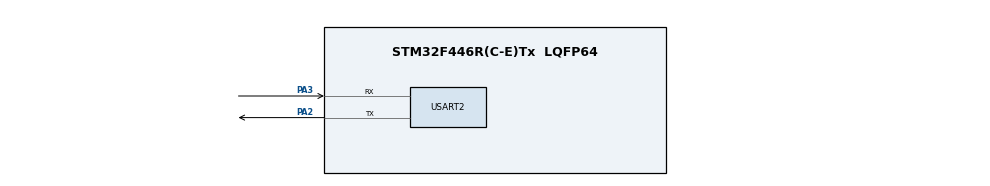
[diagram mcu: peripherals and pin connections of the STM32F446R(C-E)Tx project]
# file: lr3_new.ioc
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Mcu.Family=STM32F4
RCC.VCOOutputFreq_Value=192000000
RCC.CortexFreq_Value=16000000
Mcu.Name=STM32F446R(C-E)Tx
PA2.Signal=USART2_TX
NVIC.USART2_IRQn=true\:0\:0\:false\:false\:true\:true\:true
Mcu.Package=LQFP64
ProjectManager.StackSize=0x400
USART2.VirtualMode=VM_ASYNC
PA3.Mode=Asynchronous
ProjectManager.HeapSize=0x200
ProjectManager.TargetToolchain=STM32CubeIDE
NVIC.PriorityGroup=NVIC_PRIORITYGROUP_4
PA2.Mode=Asynchronous
RCC.USBFreq_Value=96000000
PA3.Signal=USART2_RX
board=custom

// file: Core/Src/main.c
/* USER CODE BEGIN Header */
/**
  ******************************************************************************
  * @file           : main.c
  * @brief          : Main program body
  ******************************************************************************
  * @attention
  *
  * <h2><center>&copy; Copyright (c) 2022 STMicroelectronics.
  * All rights reserved.</center></h2>
  *
  * This software component is licensed by ST under BSD 3-Clause license,
  * the "License"; You may not use this file except in compliance with the
  * License. You may obtain a copy of the License at:
  *                        opensource.org/licenses/BSD-3-Clause
  *
  ******************************************************************************
  */
/* USER CODE END Header */
#include "main.h"
#include <stdlib.h>
#include <math.h>
#include <string.h>
#include <stdint.h>

UART_HandleTypeDef huart2;

void SystemClock_Config(void);
static void MX_GPIO_Init(void);
static void MX_USART2_UART_Init(void);

/* USER CODE BEGIN 0 */

void set_number(int64_t);
void reset_number();
void set_screen(int64_t);
void set_minus(int64_t);
void set_long_number(int64_t);
void reset_all();
int64_t unpack_data(uint8_t*);
void pack_data(double) ;
void set_to_empty(uint8_t*, uint16_t);
void set_float_number(double);
int64_t get_float_part(double);
void add_minus();
void add_number(int64_t);
void add_dot();
void set_dot();

/* USER CODE END 0 */

int64_t count = 0;
double answer = 0;
uint8_t input_data[] = {'N', 0, 0, 0, 0, 0, 0, 'E'};
uint8_t output_data[] = {'N', 0, 0, 0, 0, 0, 50, 'E'};
uint8_t empty_data[] = {'N', 0, 0, 0, 0, 0, 0, 'E'};
uint16_t input_package_size = 8;
uint16_t output_package_size = 8;
uint8_t pos = 1;

int main(void)
{

  /* MCU Configuration--------------------------------------------------------*/

  /* Reset of all peripherals, Initializes the Flash interface and the Systick. */
  HAL_Init();

  /* Configure the system clock */
  SystemClock_Config();

  /* Initialize all configured peripherals */
  MX_GPIO_Init();
  MX_USART2_UART_Init();

  /* Infinite loop */
  /* USER CODE BEGIN WHILE */

  reset_all();
  set_long_number(count);

  HAL_UART_Receive_IT(&huart2, input_data, input_package_size);

  while (1)
  {

	//  HAL_UART_Transmit_IT(&huart2, output_data, output_package_size);
	  HAL_Delay(1);
	  set_float_number(answer);

    /* USER CODE END WHILE */

  }
}

int64_t unpack_data(uint8_t* data){
	return (int64_t)((100000*(int64_t)(data[1] - '0'))+(10000*(int64_t)(data[2] - '0')) + (1000*(int64_t)(data[4] - '0')) + (100*(int64_t)(data[4] - '0'))+(10*(int64_t)(data[5] - '0')) + (int64_t)(data[6]-'0'));
}

void pack_data(double data) {
	if (data < 0) add_minus();
	if (abs(data) == 1) {
		add_number(1);
	} else {
		add_number(0);
		add_dot();
		add_number((int)(abs(data*1000)));
	}

}

void add_minus() {
	output_data[pos] = 45;
	pos++;
}

void add_dot() {
	output_data[pos] = 46;
	pos++;
}

void add_number(int64_t num) {
	if (num == 0) {
		output_data[pos] = 48;
		pos++;
		return;
	}

	int64_t buffer = num;
	int64_t digit_count = 0;

	for (int i = 1; i <= 5; ++i) {
	    if (buffer % 10) digit_count = i;
	    buffer /= 10;
	}

	int64_t counter = 0;
	int64_t module = pow(10, digit_count-1);

	while (counter < digit_count) {
		output_data[pos] = num / module + 48;
		num = num % module;
		module = module/10;
		counter++;
		pos++;
	}
}

void set_to_empty(uint8_t* array, uint16_t input_package_size) {
	for (int64_t i = 1; i < input_package_size-1; i++) {
		array[i] = 0;
	}
}

void set_number(int64_t num) {
    switch (num) {
        case 0:
            HAL_GPIO_WritePin(GPIOD, GPIO_PIN_2, GPIO_PIN_RESET);
            HAL_GPIO_WritePin(GPIOA, GPIO_PIN_6, GPIO_PIN_RESET);
            HAL_GPIO_WritePin(GPIOA, GPIO_PIN_12, GPIO_PIN_RESET);
            HAL_GPIO_WritePin(GPIOA, GPIO_PIN_11, GPIO_PIN_RESET);
            HAL_GPIO_WritePin(GPIOC, GPIO_PIN_10, GPIO_PIN_RESET);
            HAL_GPIO_WritePin(GPIOC, GPIO_PIN_11, GPIO_PIN_RESET);
            break;
        case 1:
            HAL_GPIO_WritePin(GPIOA, GPIO_PIN_12, GPIO_PIN_RESET);
	        HAL_GPIO_WritePin(GPIOA, GPIO_PIN_11, GPIO_PIN_RESET);
            break;
        case 2:
            HAL_GPIO_WritePin(GPIOC, GPIO_PIN_12, GPIO_PIN_RESET);
	        HAL_GPIO_WritePin(GPIOA, GPIO_PIN_6, GPIO_PIN_RESET);
	        HAL_GPIO_WritePin(GPIOA, GPIO_PIN_12, GPIO_PIN_RESET);
	        HAL_GPIO_WritePin(GPIOC, GPIO_PIN_10, GPIO_PIN_RESET);
	        HAL_GPIO_WritePin(GPIOC, GPIO_PIN_11, GPIO_PIN_RESET);
            break;
        case 3:
            HAL_GPIO_WritePin(GPIOC, GPIO_PIN_12, GPIO_PIN_RESET);
            HAL_GPIO_WritePin(GPIOA, GPIO_PIN_6, GPIO_PIN_RESET);
            HAL_GPIO_WritePin(GPIOA, GPIO_PIN_12, GPIO_PIN_RESET);
            HAL_GPIO_WritePin(GPIOC, GPIO_PIN_10, GPIO_PIN_RESET);
            HAL_GPIO_WritePin(GPIOA, GPIO_PIN_11, GPIO_PIN_RESET);
            break;
        case 4:
            HAL_GPIO_WritePin(GPIOD, GPIO_PIN_2, GPIO_PIN_RESET);
	        HAL_GPIO_WritePin(GPIOC, GPIO_PIN_12, GPIO_PIN_RESET);
	        HAL_GPIO_WritePin(GPIOA, GPIO_PIN_12, GPIO_PIN_RESET);
	        HAL_GPIO_WritePin(GPIOA, GPIO_PIN_11, GPIO_PIN_RESET);
            break;
        case 5:
            HAL_GPIO_WritePin(GPIOC, GPIO_PIN_12, GPIO_PIN_RESET);
            HAL_GPIO_WritePin(GPIOD, GPIO_PIN_2, GPIO_PIN_RESET);
            HAL_GPIO_WritePin(GPIOA, GPIO_PIN_6, GPIO_PIN_RESET);
            HAL_GPIO_WritePin(GPIOA, GPIO_PIN_11, GPIO_PIN_RESET);
            HAL_GPIO_WritePin(GPIOC, GPIO_PIN_10, GPIO_PIN_RESET);
            break;
        case 6:
            HAL_GPIO_WritePin(GPIOC, GPIO_PIN_12, GPIO_PIN_RESET);
            HAL_GPIO_WritePin(GPIOD, GPIO_PIN_2, GPIO_PIN_RESET);
            HAL_GPIO_WritePin(GPIOA, GPIO_PIN_6, GPIO_PIN_RESET);
            HAL_GPIO_WritePin(GPIOA, GPIO_PIN_11, GPIO_PIN_RESET);
            HAL_GPIO_WritePin(GPIOC, GPIO_PIN_10, GPIO_PIN_RESET);
            HAL_GPIO_WritePin(GPIOC, GPIO_PIN_11, GPIO_PIN_RESET);
            break;
        case 7:
            HAL_GPIO_WritePin(GPIOA, GPIO_PIN_6, GPIO_PIN_RESET);
            HAL_GPIO_WritePin(GPIOA, GPIO_PIN_12, GPIO_PIN_RESET);
            HAL_GPIO_WritePin(GPIOA, GPIO_PIN_11, GPIO_PIN_RESET);
            break;
        case 8:
            HAL_GPIO_WritePin(GPIOC, GPIO_PIN_12, GPIO_PIN_RESET);
            HAL_GPIO_WritePin(GPIOD, GPIO_PIN_2, GPIO_PIN_RESET);
            HAL_GPIO_WritePin(GPIOA, GPIO_PIN_6, GPIO_PIN_RESET);
            HAL_GPIO_WritePin(GPIOA, GPIO_PIN_12, GPIO_PIN_RESET);
            HAL_GPIO_WritePin(GPIOA, GPIO_PIN_11, GPIO_PIN_RESET);
            HAL_GPIO_WritePin(GPIOC, GPIO_PIN_10, GPIO_PIN_RESET);
            HAL_GPIO_WritePin(GPIOC, GPIO_PIN_11, GPIO_PIN_RESET);
            break;
        case 9:
            HAL_GPIO_WritePin(GPIOC, GPIO_PIN_12, GPIO_PIN_RESET);
            HAL_GPIO_WritePin(GPIOD, GPIO_PIN_2, GPIO_PIN_RESET);
            HAL_GPIO_WritePin(GPIOA, GPIO_PIN_6, GPIO_PIN_RESET);
            HAL_GPIO_WritePin(GPIOA, GPIO_PIN_12, GPIO_PIN_RESET);
            HAL_GPIO_WritePin(GPIOA, GPIO_PIN_11, GPIO_PIN_RESET);
            HAL_GPIO_WritePin(GPIOC, GPIO_PIN_10, GPIO_PIN_RESET);
            break;
    }
}

void reset_number() {
    HAL_GPIO_WritePin(GPIOC, GPIO_PIN_12, GPIO_PIN_SET);
    HAL_GPIO_WritePin(GPIOD, GPIO_PIN_2, GPIO_PIN_SET);
    HAL_GPIO_WritePin(GPIOA, GPIO_PIN_6, GPIO_PIN_SET);
    HAL_GPIO_WritePin(GPIOA, GPIO_PIN_12, GPIO_PIN_SET);
    HAL_GPIO_WritePin(GPIOA, GPIO_PIN_11, GPIO_PIN_SET);
    HAL_GPIO_WritePin(GPIOC, GPIO_PIN_10, GPIO_PIN_SET);
    HAL_GPIO_WritePin(GPIOC, GPIO_PIN_11, GPIO_PIN_SET);
    HAL_GPIO_WritePin(GPIOA, GPIO_PIN_15, GPIO_PIN_SET);
}

void set_screen(int64_t num) {
    switch (num) {
        case 1:
            HAL_GPIO_WritePin(GPIOB, GPIO_PIN_1, GPIO_PIN_SET);
            HAL_GPIO_WritePin(GPIOB, GPIO_PIN_3, GPIO_PIN_SET);
            HAL_GPIO_WritePin(GPIOA, GPIO_PIN_10, GPIO_PIN_SET);
            HAL_GPIO_WritePin(GPIOC, GPIO_PIN_4, GPIO_PIN_RESET);
            break;
        case 2:
            HAL_GPIO_WritePin(GPIOB, GPIO_PIN_1, GPIO_PIN_SET);
            HAL_GPIO_WritePin(GPIOB, GPIO_PIN_3, GPIO_PIN_SET);
            HAL_GPIO_WritePin(GPIOA, GPIO_PIN_10, GPIO_PIN_RESET);
            HAL_GPIO_WritePin(GPIOC, GPIO_PIN_4, GPIO_PIN_SET);
            break;
        case 3:
            HAL_GPIO_WritePin(GPIOB, GPIO_PIN_1, GPIO_PIN_SET);
            HAL_GPIO_WritePin(GPIOB, GPIO_PIN_3, GPIO_PIN_RESET);
            HAL_GPIO_WritePin(GPIOA, GPIO_PIN_10, GPIO_PIN_SET);
            HAL_GPIO_WritePin(GPIOC, GPIO_PIN_4, GPIO_PIN_SET);
            break;
        case 4:
            HAL_GPIO_WritePin(GPIOB, GPIO_PIN_1, GPIO_PIN_RESET);
            HAL_GPIO_WritePin(GPIOB, GPIO_PIN_3, GPIO_PIN_SET);
            HAL_GPIO_WritePin(GPIOA, GPIO_PIN_10, GPIO_PIN_SET);
            HAL_GPIO_WritePin(GPIOC, GPIO_PIN_4, GPIO_PIN_SET);
            break;
    }
}

void set_long_number(int64_t num) {

    int64_t digit_count = 0;
    int64_t buffer = (int64_t) abs(num);

    for (int i = 1; i <= 4; ++i) {
        if (buffer % 10) digit_count = i;
        buffer /= 10;
    }

    if (num == 0) {
    	digit_count = 2;
    }

    buffer = (int64_t) abs(num);

    for (int i = 1; i <= digit_count; ++i) {
        set_screen(i);
        reset_number();
        set_number(buffer % 10);
        buffer /= 10;
        HAL_Delay(1);
        if (num < 0) {
                set_minus(digit_count+1);
				HAL_Delay(1);
        }
    }

}

void reset_all() {
    for (int i = 1; i <= 4; ++i) {
        set_screen(i);
        reset_number();
    }
}

void set_minus(int64_t digit_count) {
    set_screen(digit_count+1);
    reset_number();
    HAL_GPIO_WritePin(GPIOC, GPIO_PIN_12, GPIO_PIN_RESET);
}

void set_float_number(double num) {
	int64_t int_part = (int)num;
	int64_t float_part = get_float_part(num);
	if (int_part < 0) {
		set_minus(4);
	}
	HAL_Delay(1);
	set_screen(3);
	reset_number();
	set_number(int_part);
	set_dot();
	HAL_Delay(1);
	set_long_number(float_part);
}

int64_t get_float_part(double num) {
	num = num - (double)((int)num);
	return ((int)(round(num*100)));
}

void set_dot() {
	HAL_GPIO_WritePin(GPIOA, GPIO_PIN_15, GPIO_PIN_RESET);
}

void SystemClock_Config(void)
{
  RCC_OscInitTypeDef RCC_OscInitStruct = {0};
  RCC_ClkInitTypeDef RCC_ClkInitStruct = {0};

  /** Configure the main internal regulator output voltage
  */
  __HAL_RCC_PWR_CLK_ENABLE();
  __HAL_PWR_VOLTAGESCALING_CONFIG(PWR_REGULATOR_VOLTAGE_SCALE3);
  /** Initializes the RCC Oscillators according to the specified parameters
  * in the RCC_OscInitTypeDef structure.
  */
  RCC_OscInitStruct.OscillatorType = RCC_OSCILLATORTYPE_HSI;
  RCC_OscInitStruct.HSIState = RCC_HSI_ON;
  RCC_OscInitStruct.HSICalibrationValue = RCC_HSICALIBRATION_DEFAULT;
  RCC_OscInitStruct.PLL.PLLState = RCC_PLL_NONE;
  if (HAL_RCC_OscConfig(&RCC_OscInitStruct) != HAL_OK)
  {
    Error_Handler();
  }
  /** Initializes the CPU, AHB and APB buses clocks
  */
  RCC_ClkInitStruct.ClockType = RCC_CLOCKTYPE_HCLK|RCC_CLOCKTYPE_SYSCLK
                              |RCC_CLOCKTYPE_PCLK1|RCC_CLOCKTYPE_PCLK2;
  RCC_ClkInitStruct.SYSCLKSource = RCC_SYSCLKSOURCE_HSI;
  RCC_ClkInitStruct.AHBCLKDivider = RCC_SYSCLK_DIV1;
  RCC_ClkInitStruct.APB1CLKDivider = RCC_HCLK_DIV1;
  RCC_ClkInitStruct.APB2CLKDivider = RCC_HCLK_DIV1;

  if (HAL_RCC_ClockConfig(&RCC_ClkInitStruct, FLASH_LATENCY_0) != HAL_OK)
  {
    Error_Handler();
  }
}

static void MX_USART2_UART_Init(void)
{

  huart2.Instance = USART2;
  huart2.Init.BaudRate = 115200;
  huart2.Init.WordLength = UART_WORDLENGTH_8B;
  huart2.Init.StopBits = UART_STOPBITS_1;
  huart2.Init.Parity = UART_PARITY_NONE;
  huart2.Init.Mode = UART_MODE_TX_RX;
  huart2.Init.HwFlowCtl = UART_HWCONTROL_NONE;
  huart2.Init.OverSampling = UART_OVERSAMPLING_16;
  if (HAL_UART_Init(&huart2) != HAL_OK)
  {
    Error_Handler();
  }

}

static void MX_GPIO_Init(void)
{

  /* GPIO Ports Clock Enable */
  __HAL_RCC_GPIOA_CLK_ENABLE();
  GPIO_InitTypeDef GPIO_InitStruct = {0};

  /* GPIO Ports Clock Enable */
  __HAL_RCC_GPIOA_CLK_ENABLE();
  __HAL_RCC_GPIOC_CLK_ENABLE();
  __HAL_RCC_GPIOB_CLK_ENABLE();
  __HAL_RCC_GPIOD_CLK_ENABLE();

  /*Configure GPIO pin Output Level */
  HAL_GPIO_WritePin(GPIOA, GPIO_PIN_6|GPIO_PIN_10|GPIO_PIN_11|GPIO_PIN_12
                          |GPIO_PIN_15, GPIO_PIN_RESET);

  /*Configure GPIO pin Output Level */
  HAL_GPIO_WritePin(GPIOC, GPIO_PIN_4|GPIO_PIN_10|GPIO_PIN_11|GPIO_PIN_12, GPIO_PIN_RESET);

  /*Configure GPIO pin Output Level */
  HAL_GPIO_WritePin(GPIOB, GPIO_PIN_1|GPIO_PIN_3, GPIO_PIN_RESET);

  /*Configure GPIO pin Output Level */
  HAL_GPIO_WritePin(GPIOD, GPIO_PIN_2, GPIO_PIN_RESET);

  /*Configure GPIO pins : PA6 PA10 PA11 PA12
                           PA15 */
  GPIO_InitStruct.Pin = GPIO_PIN_6|GPIO_PIN_10|GPIO_PIN_11|GPIO_PIN_12
                          |GPIO_PIN_15;
  GPIO_InitStruct.Mode = GPIO_MODE_OUTPUT_PP;
  GPIO_InitStruct.Pull = GPIO_NOPULL;
  GPIO_InitStruct.Speed = GPIO_SPEED_FREQ_LOW;
  HAL_GPIO_Init(GPIOA, &GPIO_InitStruct);

  /*Configure GPIO pins : PC4 PC10 PC11 PC12 */
  GPIO_InitStruct.Pin = GPIO_PIN_4|GPIO_PIN_10|GPIO_PIN_11|GPIO_PIN_12;
  GPIO_InitStruct.Mode = GPIO_MODE_OUTPUT_PP;
  GPIO_InitStruct.Pull = GPIO_NOPULL;
  GPIO_InitStruct.Speed = GPIO_SPEED_FREQ_LOW;
  HAL_GPIO_Init(GPIOC, &GPIO_InitStruct);

  /*Configure GPIO pins : PB1 PB3 */
  GPIO_InitStruct.Pin = GPIO_PIN_1|GPIO_PIN_3;
  GPIO_InitStruct.Mode = GPIO_MODE_OUTPUT_PP;
  GPIO_InitStruct.Pull = GPIO_NOPULL;
  GPIO_InitStruct.Speed = GPIO_SPEED_FREQ_LOW;
  HAL_GPIO_Init(GPIOB, &GPIO_InitStruct);

  /*Configure GPIO pin : PD2 */
  GPIO_InitStruct.Pin = GPIO_PIN_2;
  GPIO_InitStruct.Mode = GPIO_MODE_OUTPUT_PP;
  GPIO_InitStruct.Pull = GPIO_NOPULL;
  GPIO_InitStruct.Speed = GPIO_SPEED_FREQ_LOW;
  HAL_GPIO_Init(GPIOD, &GPIO_InitStruct);

}

/* USER CODE BEGIN 4 */
/*
void HAL_UART_RxCpltCallback(UART_HandleTypeDef *huart)
{
	HAL_UART_Transmit_IT(&huart2, output_data, output_package_size);
}
*/

void HAL_UART_RxCpltCallback(UART_HandleTypeDef *huart) {
	count = unpack_data(input_data);
	answer = sin(count);
	pack_data(answer);
    HAL_UART_Transmit_IT(&huart2, output_data, output_package_size);
    pos = 0;
    HAL_UART_Receive_IT(&huart2, input_data, input_package_size);
}

/* USER CODE END 4 */

void Error_Handler(void)
{
  __disable_irq();
  while (1)
  {
  }
}

/************************ (C) COPYRIGHT STMicroelectronics *****END OF FILE****/
